VERSION 5.7 ;
  NOWIREEXTENSIONATPIN ON ;
  DIVIDERCHAR "/" ;
  BUSBITCHARS "[]" ;
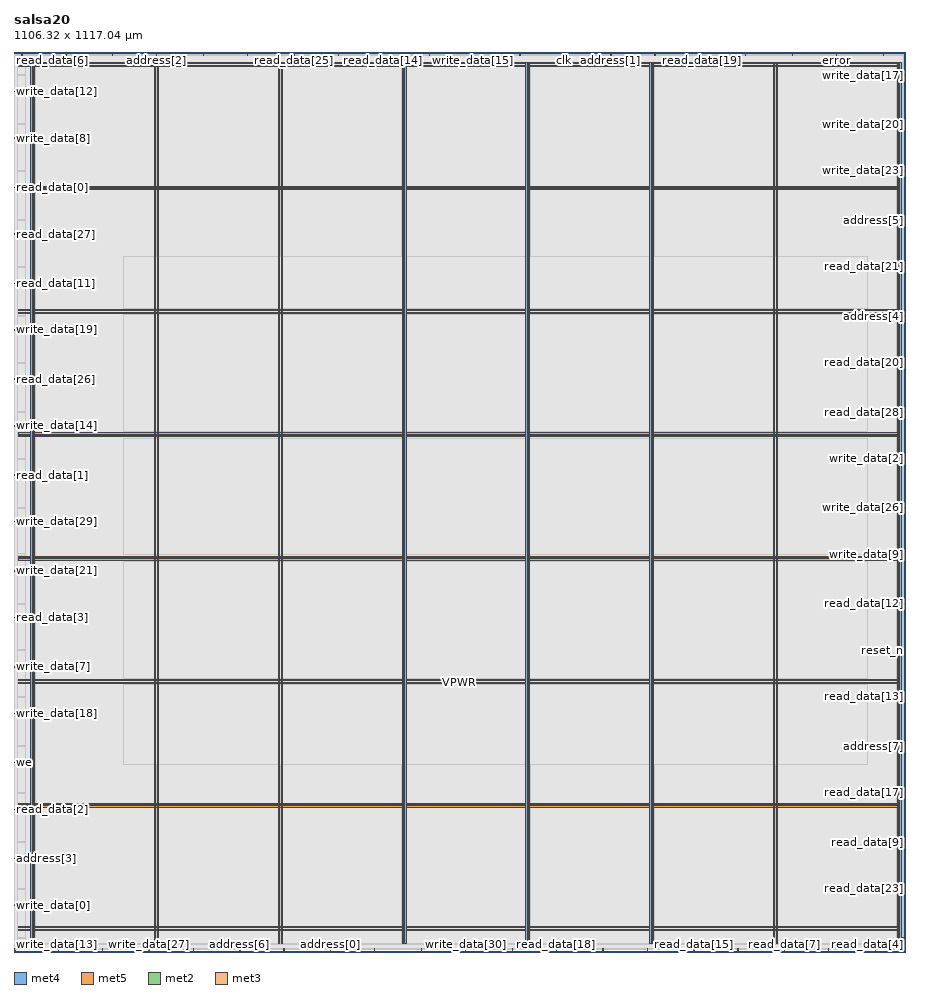
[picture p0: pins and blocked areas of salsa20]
MACRO salsa20
  CLASS BLOCK ;
  FOREIGN salsa20 ;
  ORIGIN 0.000 0.000 ;
  SIZE 1106.315 BY 1117.035 ;
  PIN VGND
    DIRECTION INOUT ;
    USE GROUND ;
    PORT
      LAYER met4 ;
        RECT 24.340 10.640 25.940 1104.560 ;
    END
    PORT
      LAYER met4 ;
        RECT 177.940 10.640 179.540 1104.560 ;
    END
    PORT
      LAYER met4 ;
        RECT 331.540 10.640 333.140 1104.560 ;
    END
    PORT
      LAYER met4 ;
        RECT 485.140 10.640 486.740 1104.560 ;
    END
    PORT
      LAYER met4 ;
        RECT 638.740 10.640 640.340 1104.560 ;
    END
    PORT
      LAYER met4 ;
        RECT 792.340 10.640 793.940 1104.560 ;
    END
    PORT
      LAYER met4 ;
        RECT 945.940 10.640 947.540 1104.560 ;
    END
    PORT
      LAYER met4 ;
        RECT 1099.540 10.640 1101.140 1104.560 ;
    END
    PORT
      LAYER met5 ;
        RECT 5.280 30.030 1101.140 31.630 ;
    END
    PORT
      LAYER met5 ;
        RECT 5.280 183.210 1101.140 184.810 ;
    END
    PORT
      LAYER met5 ;
        RECT 5.280 336.390 1101.140 337.990 ;
    END
    PORT
      LAYER met5 ;
        RECT 5.280 489.570 1101.140 491.170 ;
    END
    PORT
      LAYER met5 ;
        RECT 5.280 642.750 1101.140 644.350 ;
    END
    PORT
      LAYER met5 ;
        RECT 5.280 795.930 1101.140 797.530 ;
    END
    PORT
      LAYER met5 ;
        RECT 5.280 949.110 1101.140 950.710 ;
    END
    PORT
      LAYER met5 ;
        RECT 5.280 1102.290 1101.140 1103.890 ;
    END
  END VGND
  PIN VPWR
    DIRECTION INOUT ;
    USE POWER ;
    PORT
      LAYER met4 ;
        RECT 21.040 10.640 22.640 1104.560 ;
    END
    PORT
      LAYER met4 ;
        RECT 174.640 10.640 176.240 1104.560 ;
    END
    PORT
      LAYER met4 ;
        RECT 328.240 10.640 329.840 1104.560 ;
    END
    PORT
      LAYER met4 ;
        RECT 481.840 10.640 483.440 1104.560 ;
    END
    PORT
      LAYER met4 ;
        RECT 635.440 10.640 637.040 1104.560 ;
    END
    PORT
      LAYER met4 ;
        RECT 789.040 10.640 790.640 1104.560 ;
    END
    PORT
      LAYER met4 ;
        RECT 942.640 10.640 944.240 1104.560 ;
    END
    PORT
      LAYER met4 ;
        RECT 1096.240 10.640 1097.840 1104.560 ;
    END
    PORT
      LAYER met5 ;
        RECT 5.280 26.730 1101.020 28.330 ;
    END
    PORT
      LAYER met5 ;
        RECT 5.280 179.910 1101.020 181.510 ;
    END
    PORT
      LAYER met5 ;
        RECT 5.280 333.090 1101.020 334.690 ;
    END
    PORT
      LAYER met5 ;
        RECT 5.280 486.270 1101.020 487.870 ;
    END
    PORT
      LAYER met5 ;
        RECT 5.280 639.450 1101.020 641.050 ;
    END
    PORT
      LAYER met5 ;
        RECT 5.280 792.630 1101.020 794.230 ;
    END
    PORT
      LAYER met5 ;
        RECT 5.280 945.810 1101.020 947.410 ;
    END
    PORT
      LAYER met5 ;
        RECT 5.280 1098.990 1101.020 1100.590 ;
    END
  END VPWR
  PIN address[0]
    DIRECTION INPUT ;
    USE SIGNAL ;
    ANTENNAGATEAREA 0.593700 ;
    ANTENNADIFFAREA 0.434700 ;
    PORT
      LAYER met2 ;
        RECT 392.930 0.000 393.210 4.000 ;
    END
  END address[0]
  PIN address[1]
    DIRECTION INPUT ;
    USE SIGNAL ;
    ANTENNAGATEAREA 1.177200 ;
    ANTENNADIFFAREA 0.434700 ;
    PORT
      LAYER met2 ;
        RECT 740.690 1113.035 740.970 1117.035 ;
    END
  END address[1]
  PIN address[2]
    DIRECTION INPUT ;
    USE SIGNAL ;
    ANTENNAGATEAREA 1.177200 ;
    ANTENNADIFFAREA 0.434700 ;
    PORT
      LAYER met2 ;
        RECT 177.190 1113.035 177.470 1117.035 ;
    END
  END address[2]
  PIN address[3]
    DIRECTION INPUT ;
    USE SIGNAL ;
    ANTENNAGATEAREA 0.682200 ;
    ANTENNADIFFAREA 0.434700 ;
    PORT
      LAYER met3 ;
        RECT 0.000 115.640 4.000 116.240 ;
    END
  END address[3]
  PIN address[4]
    DIRECTION INPUT ;
    USE SIGNAL ;
    ANTENNAGATEAREA 1.177200 ;
    ANTENNADIFFAREA 0.434700 ;
    PORT
      LAYER met3 ;
        RECT 1102.315 788.840 1106.315 789.440 ;
    END
  END address[4]
  PIN address[5]
    DIRECTION INPUT ;
    USE SIGNAL ;
    ANTENNAGATEAREA 1.286700 ;
    ANTENNADIFFAREA 0.434700 ;
    PORT
      LAYER met3 ;
        RECT 1102.315 907.840 1106.315 908.440 ;
    END
  END address[5]
  PIN address[6]
    DIRECTION INPUT ;
    USE SIGNAL ;
    ANTENNAGATEAREA 0.647700 ;
    ANTENNADIFFAREA 0.434700 ;
    PORT
      LAYER met2 ;
        RECT 280.230 0.000 280.510 4.000 ;
    END
  END address[6]
  PIN address[7]
    DIRECTION INPUT ;
    USE SIGNAL ;
    ANTENNAGATEAREA 0.860700 ;
    ANTENNADIFFAREA 0.434700 ;
    PORT
      LAYER met3 ;
        RECT 1102.315 255.040 1106.315 255.640 ;
    END
  END address[7]
  PIN clk
    DIRECTION INPUT ;
    USE SIGNAL ;
    ANTENNAGATEAREA 1.286700 ;
    ANTENNADIFFAREA 0.434700 ;
    PORT
      LAYER met2 ;
        RECT 682.730 1113.035 683.010 1117.035 ;
    END
  END clk
  PIN cs
    DIRECTION INPUT ;
    USE SIGNAL ;
    ANTENNAGATEAREA 1.177200 ;
    ANTENNADIFFAREA 0.434700 ;
    PORT
      LAYER met2 ;
        RECT 64.490 1113.035 64.770 1117.035 ;
    END
  END cs
  PIN error
    DIRECTION OUTPUT TRISTATE ;
    USE SIGNAL ;
    ANTENNADIFFAREA 0.795200 ;
    PORT
      LAYER met2 ;
        RECT 1020.830 1113.035 1021.110 1117.035 ;
    END
  END error
  PIN read_data[0]
    DIRECTION OUTPUT TRISTATE ;
    USE SIGNAL ;
    ANTENNADIFFAREA 0.795200 ;
    PORT
      LAYER met3 ;
        RECT 0.000 948.640 4.000 949.240 ;
    END
  END read_data[0]
  PIN read_data[10]
    DIRECTION OUTPUT TRISTATE ;
    USE SIGNAL ;
    ANTENNADIFFAREA 0.795200 ;
    PORT
      LAYER met2 ;
        RECT 1011.170 0.000 1011.450 4.000 ;
    END
  END read_data[10]
  PIN read_data[11]
    DIRECTION OUTPUT TRISTATE ;
    USE SIGNAL ;
    ANTENNADIFFAREA 0.795200 ;
    PORT
      LAYER met3 ;
        RECT 0.000 829.640 4.000 830.240 ;
    END
  END read_data[11]
  PIN read_data[12]
    DIRECTION OUTPUT TRISTATE ;
    USE SIGNAL ;
    ANTENNADIFFAREA 0.445500 ;
    PORT
      LAYER met3 ;
        RECT 1102.315 431.840 1106.315 432.440 ;
    END
  END read_data[12]
  PIN read_data[13]
    DIRECTION OUTPUT TRISTATE ;
    USE SIGNAL ;
    ANTENNADIFFAREA 0.445500 ;
    PORT
      LAYER met3 ;
        RECT 1102.315 316.240 1106.315 316.840 ;
    END
  END read_data[13]
  PIN read_data[14]
    DIRECTION OUTPUT TRISTATE ;
    USE SIGNAL ;
    ANTENNADIFFAREA 0.795200 ;
    PORT
      LAYER met2 ;
        RECT 457.330 1113.035 457.610 1117.035 ;
    END
  END read_data[14]
  PIN read_data[15]
    DIRECTION OUTPUT TRISTATE ;
    USE SIGNAL ;
    ANTENNADIFFAREA 0.795200 ;
    PORT
      LAYER met2 ;
        RECT 843.730 0.000 844.010 4.000 ;
    END
  END read_data[15]
  PIN read_data[16]
    DIRECTION OUTPUT TRISTATE ;
    USE SIGNAL ;
    ANTENNADIFFAREA 0.795200 ;
    PORT
      LAYER met2 ;
        RECT 1078.790 1113.035 1079.070 1117.035 ;
    END
  END read_data[16]
  PIN read_data[17]
    DIRECTION OUTPUT TRISTATE ;
    USE SIGNAL ;
    ANTENNADIFFAREA 0.445500 ;
    PORT
      LAYER met3 ;
        RECT 1102.315 197.240 1106.315 197.840 ;
    END
  END read_data[17]
  PIN read_data[18]
    DIRECTION OUTPUT TRISTATE ;
    USE SIGNAL ;
    ANTENNADIFFAREA 0.795200 ;
    PORT
      LAYER met2 ;
        RECT 673.070 0.000 673.350 4.000 ;
    END
  END read_data[18]
  PIN read_data[19]
    DIRECTION OUTPUT TRISTATE ;
    USE SIGNAL ;
    ANTENNADIFFAREA 0.795200 ;
    PORT
      LAYER met2 ;
        RECT 853.390 1113.035 853.670 1117.035 ;
    END
  END read_data[19]
  PIN read_data[1]
    DIRECTION OUTPUT TRISTATE ;
    USE SIGNAL ;
    ANTENNADIFFAREA 0.795200 ;
    PORT
      LAYER met3 ;
        RECT 0.000 591.640 4.000 592.240 ;
    END
  END read_data[1]
  PIN read_data[20]
    DIRECTION OUTPUT TRISTATE ;
    USE SIGNAL ;
    ANTENNADIFFAREA 0.445500 ;
    PORT
      LAYER met3 ;
        RECT 1102.315 731.040 1106.315 731.640 ;
    END
  END read_data[20]
  PIN read_data[21]
    DIRECTION OUTPUT TRISTATE ;
    USE SIGNAL ;
    ANTENNADIFFAREA 0.445500 ;
    PORT
      LAYER met3 ;
        RECT 1102.315 850.040 1106.315 850.640 ;
    END
  END read_data[21]
  PIN read_data[22]
    DIRECTION OUTPUT TRISTATE ;
    USE SIGNAL ;
    ANTENNADIFFAREA 0.795200 ;
    PORT
      LAYER met2 ;
        RECT 898.470 0.000 898.750 4.000 ;
    END
  END read_data[22]
  PIN read_data[23]
    DIRECTION OUTPUT TRISTATE ;
    USE SIGNAL ;
    ANTENNADIFFAREA 0.445500 ;
    PORT
      LAYER met3 ;
        RECT 1102.315 78.240 1106.315 78.840 ;
    END
  END read_data[23]
  PIN read_data[24]
    DIRECTION OUTPUT TRISTATE ;
    USE SIGNAL ;
    ANTENNADIFFAREA 0.795200 ;
    PORT
      LAYER met2 ;
        RECT 109.570 0.000 109.850 4.000 ;
    END
  END read_data[24]
  PIN read_data[25]
    DIRECTION OUTPUT TRISTATE ;
    USE SIGNAL ;
    ANTENNADIFFAREA 0.795200 ;
    PORT
      LAYER met2 ;
        RECT 347.850 1113.035 348.130 1117.035 ;
    END
  END read_data[25]
  PIN read_data[26]
    DIRECTION OUTPUT TRISTATE ;
    USE SIGNAL ;
    ANTENNADIFFAREA 0.795200 ;
    PORT
      LAYER met3 ;
        RECT 0.000 710.640 4.000 711.240 ;
    END
  END read_data[26]
  PIN read_data[27]
    DIRECTION OUTPUT TRISTATE ;
    USE SIGNAL ;
    ANTENNADIFFAREA 0.795200 ;
    PORT
      LAYER met3 ;
        RECT 0.000 890.840 4.000 891.440 ;
    END
  END read_data[27]
  PIN read_data[28]
    DIRECTION OUTPUT TRISTATE ;
    USE SIGNAL ;
    ANTENNADIFFAREA 0.795200 ;
    PORT
      LAYER met3 ;
        RECT 1102.315 669.840 1106.315 670.440 ;
    END
  END read_data[28]
  PIN read_data[29]
    DIRECTION OUTPUT TRISTATE ;
    USE SIGNAL ;
    ANTENNADIFFAREA 0.795200 ;
    PORT
      LAYER met2 ;
        RECT 505.630 0.000 505.910 4.000 ;
    END
  END read_data[29]
  PIN read_data[2]
    DIRECTION OUTPUT TRISTATE ;
    USE SIGNAL ;
    ANTENNADIFFAREA 0.795200 ;
    PORT
      LAYER met3 ;
        RECT 0.000 176.840 4.000 177.440 ;
    END
  END read_data[2]
  PIN read_data[30]
    DIRECTION OUTPUT TRISTATE ;
    USE SIGNAL ;
    ANTENNADIFFAREA 0.795200 ;
    PORT
      LAYER met2 ;
        RECT 222.270 0.000 222.550 4.000 ;
    END
  END read_data[30]
  PIN read_data[31]
    DIRECTION OUTPUT TRISTATE ;
    USE SIGNAL ;
    ANTENNADIFFAREA 0.795200 ;
    PORT
      LAYER met2 ;
        RECT 785.770 0.000 786.050 4.000 ;
    END
  END read_data[31]
  PIN read_data[3]
    DIRECTION OUTPUT TRISTATE ;
    USE SIGNAL ;
    ANTENNADIFFAREA 0.795200 ;
    PORT
      LAYER met3 ;
        RECT 0.000 414.840 4.000 415.440 ;
    END
  END read_data[3]
  PIN read_data[4]
    DIRECTION OUTPUT TRISTATE ;
    USE SIGNAL ;
    ANTENNADIFFAREA 0.795200 ;
    PORT
      LAYER met2 ;
        RECT 1069.130 0.000 1069.410 4.000 ;
    END
  END read_data[4]
  PIN read_data[5]
    DIRECTION OUTPUT TRISTATE ;
    USE SIGNAL ;
    ANTENNADIFFAREA 0.795200 ;
    PORT
      LAYER met2 ;
        RECT 618.330 0.000 618.610 4.000 ;
    END
  END read_data[5]
  PIN read_data[6]
    DIRECTION OUTPUT TRISTATE ;
    USE SIGNAL ;
    ANTENNADIFFAREA 0.795200 ;
    PORT
      LAYER met2 ;
        RECT 9.750 1113.035 10.030 1117.035 ;
    END
  END read_data[6]
  PIN read_data[7]
    DIRECTION OUTPUT TRISTATE ;
    USE SIGNAL ;
    ANTENNADIFFAREA 0.795200 ;
    PORT
      LAYER met2 ;
        RECT 956.430 0.000 956.710 4.000 ;
    END
  END read_data[7]
  PIN read_data[8]
    DIRECTION OUTPUT TRISTATE ;
    USE SIGNAL ;
    ANTENNADIFFAREA 0.795200 ;
    PORT
      LAYER met2 ;
        RECT 515.290 1113.035 515.570 1117.035 ;
    END
  END read_data[8]
  PIN read_data[9]
    DIRECTION OUTPUT TRISTATE ;
    USE SIGNAL ;
    ANTENNADIFFAREA 0.445500 ;
    PORT
      LAYER met3 ;
        RECT 1102.315 136.040 1106.315 136.640 ;
    END
  END read_data[9]
  PIN reset_n
    DIRECTION INPUT ;
    USE SIGNAL ;
    ANTENNAGATEAREA 0.929700 ;
    ANTENNADIFFAREA 0.434700 ;
    PORT
      LAYER met3 ;
        RECT 1102.315 374.040 1106.315 374.640 ;
    END
  END reset_n
  PIN we
    DIRECTION INPUT ;
    USE SIGNAL ;
    ANTENNAGATEAREA 0.682200 ;
    ANTENNADIFFAREA 0.434700 ;
    PORT
      LAYER met3 ;
        RECT 0.000 234.640 4.000 235.240 ;
    END
  END we
  PIN write_data[0]
    DIRECTION INPUT ;
    USE SIGNAL ;
    ANTENNAGATEAREA 0.682200 ;
    ANTENNADIFFAREA 0.434700 ;
    PORT
      LAYER met3 ;
        RECT 0.000 57.840 4.000 58.440 ;
    END
  END write_data[0]
  PIN write_data[10]
    DIRECTION INPUT ;
    USE SIGNAL ;
    ANTENNAGATEAREA 1.424700 ;
    ANTENNADIFFAREA 0.434700 ;
    PORT
      LAYER met2 ;
        RECT 402.590 1113.035 402.870 1117.035 ;
    END
  END write_data[10]
  PIN write_data[11]
    DIRECTION INPUT ;
    USE SIGNAL ;
    ANTENNAGATEAREA 1.424700 ;
    ANTENNADIFFAREA 0.434700 ;
    PORT
      LAYER met2 ;
        RECT 627.990 1113.035 628.270 1117.035 ;
    END
  END write_data[11]
  PIN write_data[12]
    DIRECTION INPUT ;
    USE SIGNAL ;
    ANTENNAGATEAREA 1.286700 ;
    ANTENNADIFFAREA 0.434700 ;
    PORT
      LAYER met3 ;
        RECT 0.000 1067.640 4.000 1068.240 ;
    END
  END write_data[12]
  PIN write_data[13]
    DIRECTION INPUT ;
    USE SIGNAL ;
    ANTENNAGATEAREA 1.424700 ;
    ANTENNADIFFAREA 0.434700 ;
    PORT
      LAYER met2 ;
        RECT 0.090 0.000 0.370 4.000 ;
    END
  END write_data[13]
  PIN write_data[14]
    DIRECTION INPUT ;
    USE SIGNAL ;
    ANTENNAGATEAREA 1.177200 ;
    ANTENNADIFFAREA 0.434700 ;
    PORT
      LAYER met3 ;
        RECT 0.000 652.840 4.000 653.440 ;
    END
  END write_data[14]
  PIN write_data[15]
    DIRECTION INPUT ;
    USE SIGNAL ;
    ANTENNAGATEAREA 1.424700 ;
    ANTENNADIFFAREA 0.434700 ;
    PORT
      LAYER met2 ;
        RECT 570.030 1113.035 570.310 1117.035 ;
    END
  END write_data[15]
  PIN write_data[16]
    DIRECTION INPUT ;
    USE SIGNAL ;
    ANTENNAGATEAREA 1.424700 ;
    ANTENNADIFFAREA 0.434700 ;
    PORT
      LAYER met2 ;
        RECT 795.430 1113.035 795.710 1117.035 ;
    END
  END write_data[16]
  PIN write_data[17]
    DIRECTION INPUT ;
    USE SIGNAL ;
    ANTENNAGATEAREA 1.424700 ;
    ANTENNADIFFAREA 0.434700 ;
    PORT
      LAYER met3 ;
        RECT 1102.315 1088.040 1106.315 1088.640 ;
    END
  END write_data[17]
  PIN write_data[18]
    DIRECTION INPUT ;
    USE SIGNAL ;
    ANTENNAGATEAREA 1.286700 ;
    ANTENNADIFFAREA 0.434700 ;
    PORT
      LAYER met3 ;
        RECT 0.000 295.840 4.000 296.440 ;
    END
  END write_data[18]
  PIN write_data[19]
    DIRECTION INPUT ;
    USE SIGNAL ;
    ANTENNAGATEAREA 1.177200 ;
    ANTENNADIFFAREA 0.434700 ;
    PORT
      LAYER met3 ;
        RECT 0.000 771.840 4.000 772.440 ;
    END
  END write_data[19]
  PIN write_data[1]
    DIRECTION INPUT ;
    USE SIGNAL ;
    ANTENNAGATEAREA 0.682200 ;
    ANTENNADIFFAREA 0.434700 ;
    PORT
      LAYER met2 ;
        RECT 54.830 0.000 55.110 4.000 ;
    END
  END write_data[1]
  PIN write_data[20]
    DIRECTION INPUT ;
    USE SIGNAL ;
    ANTENNAGATEAREA 1.424700 ;
    ANTENNADIFFAREA 0.434700 ;
    PORT
      LAYER met3 ;
        RECT 1102.315 1026.840 1106.315 1027.440 ;
    END
  END write_data[20]
  PIN write_data[21]
    DIRECTION INPUT ;
    USE SIGNAL ;
    ANTENNAGATEAREA 1.177200 ;
    ANTENNADIFFAREA 0.434700 ;
    PORT
      LAYER met3 ;
        RECT 0.000 472.640 4.000 473.240 ;
    END
  END write_data[21]
  PIN write_data[22]
    DIRECTION INPUT ;
    USE SIGNAL ;
    ANTENNAGATEAREA 1.424700 ;
    ANTENNADIFFAREA 0.434700 ;
    PORT
      LAYER met2 ;
        RECT 447.670 0.000 447.950 4.000 ;
    END
  END write_data[22]
  PIN write_data[23]
    DIRECTION INPUT ;
    USE SIGNAL ;
    ANTENNAGATEAREA 1.424700 ;
    ANTENNADIFFAREA 0.434700 ;
    PORT
      LAYER met3 ;
        RECT 1102.315 969.040 1106.315 969.640 ;
    END
  END write_data[23]
  PIN write_data[24]
    DIRECTION INPUT ;
    USE SIGNAL ;
    ANTENNAGATEAREA 1.424700 ;
    ANTENNADIFFAREA 0.434700 ;
    PORT
      LAYER met3 ;
        RECT 1102.315 17.040 1106.315 17.640 ;
    END
  END write_data[24]
  PIN write_data[25]
    DIRECTION INPUT ;
    USE SIGNAL ;
    ANTENNAGATEAREA 1.286700 ;
    ANTENNADIFFAREA 0.434700 ;
    PORT
      LAYER met2 ;
        RECT 235.150 1113.035 235.430 1117.035 ;
    END
  END write_data[25]
  PIN write_data[26]
    DIRECTION INPUT ;
    USE SIGNAL ;
    ANTENNAGATEAREA 1.424700 ;
    ANTENNADIFFAREA 0.434700 ;
    PORT
      LAYER met3 ;
        RECT 1102.315 550.840 1106.315 551.440 ;
    END
  END write_data[26]
  PIN write_data[27]
    DIRECTION INPUT ;
    USE SIGNAL ;
    ANTENNAGATEAREA 1.424700 ;
    ANTENNADIFFAREA 0.434700 ;
    PORT
      LAYER met2 ;
        RECT 167.530 0.000 167.810 4.000 ;
    END
  END write_data[27]
  PIN write_data[28]
    DIRECTION INPUT ;
    USE SIGNAL ;
    ANTENNAGATEAREA 1.424700 ;
    ANTENNADIFFAREA 0.434700 ;
    PORT
      LAYER met2 ;
        RECT 334.970 0.000 335.250 4.000 ;
    END
  END write_data[28]
  PIN write_data[29]
    DIRECTION INPUT ;
    USE SIGNAL ;
    ANTENNAGATEAREA 1.177200 ;
    ANTENNADIFFAREA 0.434700 ;
    PORT
      LAYER met3 ;
        RECT 0.000 533.840 4.000 534.440 ;
    END
  END write_data[29]
  PIN write_data[2]
    DIRECTION INPUT ;
    USE SIGNAL ;
    ANTENNAGATEAREA 0.929700 ;
    ANTENNADIFFAREA 0.434700 ;
    PORT
      LAYER met3 ;
        RECT 1102.315 612.040 1106.315 612.640 ;
    END
  END write_data[2]
  PIN write_data[30]
    DIRECTION INPUT ;
    USE SIGNAL ;
    ANTENNAGATEAREA 1.424700 ;
    ANTENNADIFFAREA 0.434700 ;
    PORT
      LAYER met2 ;
        RECT 560.370 0.000 560.650 4.000 ;
    END
  END write_data[30]
  PIN write_data[31]
    DIRECTION INPUT ;
    USE SIGNAL ;
    ANTENNAGATEAREA 1.424700 ;
    ANTENNADIFFAREA 0.434700 ;
    PORT
      LAYER met2 ;
        RECT 966.090 1113.035 966.370 1117.035 ;
    END
  END write_data[31]
  PIN write_data[3]
    DIRECTION INPUT ;
    USE SIGNAL ;
    ANTENNAGATEAREA 0.860700 ;
    ANTENNADIFFAREA 0.434700 ;
    PORT
      LAYER met2 ;
        RECT 908.130 1113.035 908.410 1117.035 ;
    END
  END write_data[3]
  PIN write_data[4]
    DIRECTION INPUT ;
    USE SIGNAL ;
    ANTENNAGATEAREA 0.593700 ;
    ANTENNADIFFAREA 0.434700 ;
    PORT
      LAYER met2 ;
        RECT 122.450 1113.035 122.730 1117.035 ;
    END
  END write_data[4]
  PIN write_data[5]
    DIRECTION INPUT ;
    USE SIGNAL ;
    ANTENNAGATEAREA 1.424700 ;
    ANTENNADIFFAREA 0.434700 ;
    PORT
      LAYER met2 ;
        RECT 289.890 1113.035 290.170 1117.035 ;
    END
  END write_data[5]
  PIN write_data[6]
    DIRECTION INPUT ;
    USE SIGNAL ;
    ANTENNAGATEAREA 1.424700 ;
    ANTENNADIFFAREA 0.434700 ;
    PORT
      LAYER met2 ;
        RECT 731.030 0.000 731.310 4.000 ;
    END
  END write_data[6]
  PIN write_data[7]
    DIRECTION INPUT ;
    USE SIGNAL ;
    ANTENNAGATEAREA 1.177200 ;
    ANTENNADIFFAREA 0.434700 ;
    PORT
      LAYER met3 ;
        RECT 0.000 353.640 4.000 354.240 ;
    END
  END write_data[7]
  PIN write_data[8]
    DIRECTION INPUT ;
    USE SIGNAL ;
    ANTENNAGATEAREA 1.177200 ;
    ANTENNADIFFAREA 0.434700 ;
    PORT
      LAYER met3 ;
        RECT 0.000 1009.840 4.000 1010.440 ;
    END
  END write_data[8]
  PIN write_data[9]
    DIRECTION INPUT ;
    USE SIGNAL ;
    ANTENNAGATEAREA 1.424700 ;
    ANTENNADIFFAREA 0.434700 ;
    PORT
      LAYER met3 ;
        RECT 1102.315 493.040 1106.315 493.640 ;
    END
  END write_data[9]
  OBS
      LAYER li1 ;
        RECT 5.520 10.795 1100.780 1104.405 ;
      LAYER met1 ;
        RECT 0.070 8.540 1104.390 1104.560 ;
      LAYER met2 ;
        RECT 0.100 1112.755 9.470 1113.570 ;
        RECT 10.310 1112.755 64.210 1113.570 ;
        RECT 65.050 1112.755 122.170 1113.570 ;
        RECT 123.010 1112.755 176.910 1113.570 ;
        RECT 177.750 1112.755 234.870 1113.570 ;
        RECT 235.710 1112.755 289.610 1113.570 ;
        RECT 290.450 1112.755 347.570 1113.570 ;
        RECT 348.410 1112.755 402.310 1113.570 ;
        RECT 403.150 1112.755 457.050 1113.570 ;
        RECT 457.890 1112.755 515.010 1113.570 ;
        RECT 515.850 1112.755 569.750 1113.570 ;
        RECT 570.590 1112.755 627.710 1113.570 ;
        RECT 628.550 1112.755 682.450 1113.570 ;
        RECT 683.290 1112.755 740.410 1113.570 ;
        RECT 741.250 1112.755 795.150 1113.570 ;
        RECT 795.990 1112.755 853.110 1113.570 ;
        RECT 853.950 1112.755 907.850 1113.570 ;
        RECT 908.690 1112.755 965.810 1113.570 ;
        RECT 966.650 1112.755 1020.550 1113.570 ;
        RECT 1021.390 1112.755 1078.510 1113.570 ;
        RECT 1079.350 1112.755 1104.360 1113.570 ;
        RECT 0.100 4.280 1104.360 1112.755 ;
        RECT 0.650 3.670 54.550 4.280 ;
        RECT 55.390 3.670 109.290 4.280 ;
        RECT 110.130 3.670 167.250 4.280 ;
        RECT 168.090 3.670 221.990 4.280 ;
        RECT 222.830 3.670 279.950 4.280 ;
        RECT 280.790 3.670 334.690 4.280 ;
        RECT 335.530 3.670 392.650 4.280 ;
        RECT 393.490 3.670 447.390 4.280 ;
        RECT 448.230 3.670 505.350 4.280 ;
        RECT 506.190 3.670 560.090 4.280 ;
        RECT 560.930 3.670 618.050 4.280 ;
        RECT 618.890 3.670 672.790 4.280 ;
        RECT 673.630 3.670 730.750 4.280 ;
        RECT 731.590 3.670 785.490 4.280 ;
        RECT 786.330 3.670 843.450 4.280 ;
        RECT 844.290 3.670 898.190 4.280 ;
        RECT 899.030 3.670 956.150 4.280 ;
        RECT 956.990 3.670 1010.890 4.280 ;
        RECT 1011.730 3.670 1068.850 4.280 ;
        RECT 1069.690 3.670 1104.360 4.280 ;
      LAYER met3 ;
        RECT 4.000 1089.040 1102.555 1104.485 ;
        RECT 4.000 1087.640 1101.915 1089.040 ;
        RECT 4.000 1068.640 1102.555 1087.640 ;
        RECT 4.400 1067.240 1102.555 1068.640 ;
        RECT 4.000 1027.840 1102.555 1067.240 ;
        RECT 4.000 1026.440 1101.915 1027.840 ;
        RECT 4.000 1010.840 1102.555 1026.440 ;
        RECT 4.400 1009.440 1102.555 1010.840 ;
        RECT 4.000 970.040 1102.555 1009.440 ;
        RECT 4.000 968.640 1101.915 970.040 ;
        RECT 4.000 949.640 1102.555 968.640 ;
        RECT 4.400 948.240 1102.555 949.640 ;
        RECT 4.000 908.840 1102.555 948.240 ;
        RECT 4.000 907.440 1101.915 908.840 ;
        RECT 4.000 891.840 1102.555 907.440 ;
        RECT 4.400 890.440 1102.555 891.840 ;
        RECT 4.000 851.040 1102.555 890.440 ;
        RECT 4.000 849.640 1101.915 851.040 ;
        RECT 4.000 830.640 1102.555 849.640 ;
        RECT 4.400 829.240 1102.555 830.640 ;
        RECT 4.000 789.840 1102.555 829.240 ;
        RECT 4.000 788.440 1101.915 789.840 ;
        RECT 4.000 772.840 1102.555 788.440 ;
        RECT 4.400 771.440 1102.555 772.840 ;
        RECT 4.000 732.040 1102.555 771.440 ;
        RECT 4.000 730.640 1101.915 732.040 ;
        RECT 4.000 711.640 1102.555 730.640 ;
        RECT 4.400 710.240 1102.555 711.640 ;
        RECT 4.000 670.840 1102.555 710.240 ;
        RECT 4.000 669.440 1101.915 670.840 ;
        RECT 4.000 653.840 1102.555 669.440 ;
        RECT 4.400 652.440 1102.555 653.840 ;
        RECT 4.000 613.040 1102.555 652.440 ;
        RECT 4.000 611.640 1101.915 613.040 ;
        RECT 4.000 592.640 1102.555 611.640 ;
        RECT 4.400 591.240 1102.555 592.640 ;
        RECT 4.000 551.840 1102.555 591.240 ;
        RECT 4.000 550.440 1101.915 551.840 ;
        RECT 4.000 534.840 1102.555 550.440 ;
        RECT 4.400 533.440 1102.555 534.840 ;
        RECT 4.000 494.040 1102.555 533.440 ;
        RECT 4.000 492.640 1101.915 494.040 ;
        RECT 4.000 473.640 1102.555 492.640 ;
        RECT 4.400 472.240 1102.555 473.640 ;
        RECT 4.000 432.840 1102.555 472.240 ;
        RECT 4.000 431.440 1101.915 432.840 ;
        RECT 4.000 415.840 1102.555 431.440 ;
        RECT 4.400 414.440 1102.555 415.840 ;
        RECT 4.000 375.040 1102.555 414.440 ;
        RECT 4.000 373.640 1101.915 375.040 ;
        RECT 4.000 354.640 1102.555 373.640 ;
        RECT 4.400 353.240 1102.555 354.640 ;
        RECT 4.000 317.240 1102.555 353.240 ;
        RECT 4.000 315.840 1101.915 317.240 ;
        RECT 4.000 296.840 1102.555 315.840 ;
        RECT 4.400 295.440 1102.555 296.840 ;
        RECT 4.000 256.040 1102.555 295.440 ;
        RECT 4.000 254.640 1101.915 256.040 ;
        RECT 4.000 235.640 1102.555 254.640 ;
        RECT 4.400 234.240 1102.555 235.640 ;
        RECT 4.000 198.240 1102.555 234.240 ;
        RECT 4.000 196.840 1101.915 198.240 ;
        RECT 4.000 177.840 1102.555 196.840 ;
        RECT 4.400 176.440 1102.555 177.840 ;
        RECT 4.000 137.040 1102.555 176.440 ;
        RECT 4.000 135.640 1101.915 137.040 ;
        RECT 4.000 116.640 1102.555 135.640 ;
        RECT 4.400 115.240 1102.555 116.640 ;
        RECT 4.000 79.240 1102.555 115.240 ;
        RECT 4.000 77.840 1101.915 79.240 ;
        RECT 4.000 58.840 1102.555 77.840 ;
        RECT 4.400 57.440 1102.555 58.840 ;
        RECT 4.000 18.040 1102.555 57.440 ;
        RECT 4.000 16.640 1101.915 18.040 ;
        RECT 4.000 9.695 1102.555 16.640 ;
      LAYER met4 ;
        RECT 14.095 10.240 20.640 1103.465 ;
        RECT 23.040 10.240 23.940 1103.465 ;
        RECT 26.340 10.240 174.240 1103.465 ;
        RECT 176.640 10.240 177.540 1103.465 ;
        RECT 179.940 10.240 327.840 1103.465 ;
        RECT 330.240 10.240 331.140 1103.465 ;
        RECT 333.540 10.240 481.440 1103.465 ;
        RECT 483.840 10.240 484.740 1103.465 ;
        RECT 487.140 10.240 635.040 1103.465 ;
        RECT 637.440 10.240 638.340 1103.465 ;
        RECT 640.740 10.240 788.640 1103.465 ;
        RECT 791.040 10.240 791.940 1103.465 ;
        RECT 794.340 10.240 942.240 1103.465 ;
        RECT 944.640 10.240 945.540 1103.465 ;
        RECT 947.940 10.240 1095.425 1103.465 ;
        RECT 14.095 9.695 1095.425 10.240 ;
      LAYER met5 ;
        RECT 135.820 799.130 1059.260 862.700 ;
        RECT 135.820 645.950 1059.260 791.030 ;
        RECT 135.820 492.770 1059.260 637.850 ;
        RECT 135.820 339.590 1059.260 484.670 ;
        RECT 135.820 232.100 1059.260 331.490 ;
  END
END salsa20
END LIBRARY

